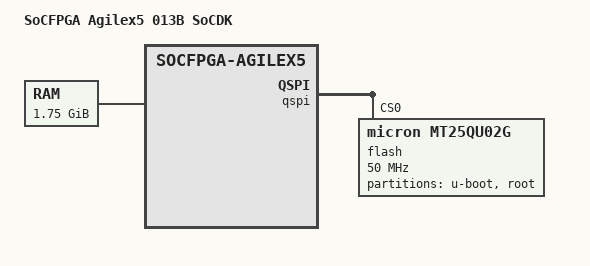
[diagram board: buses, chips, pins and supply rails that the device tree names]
// SPDX-License-Identifier: GPL-2.0-only
/*
 * Copyright (C) 2025, Altera Corporation
 */
#include "socfpga_agilex5_socdk_013b.dts"

/ {
	model = "SoCFPGA Agilex5 013B SoCDK";
	compatible = "intel,socfpga-agilex5-socdk-013b", "intel,socfpga-agilex5";

	chosen {
		stdout-path = "serial0:115200n8";
		bootargs = "console=ttys0,115200 earlycon panic=-1 root=/dev/mtdblock1 \
			rw rootfstype=jffs2 rootwait";
	};

	memory@80000000 {
		device_type = "memory";
		reg = <0 0x80000000 0 0x70000000>;
	};
};

&qspi {
	status = "okay";
	/delete-node/ flash@0;

	flash@0 {
		#address-cells = <1>;
		#size-cells = <1>;
		compatible = "micron,mt25qu02g", "jedec,spi-nor";
		reg = <0>;
		spi-max-frequency = <50000000>;
		m25p,fast-read;
		cdns,page-size = <256>;
		cdns,block-size = <16>;
		cdns,read-delay = <2>;
		cdns,tshsl-ns = <50>;
		cdns,tsd2d-ns = <50>;
		cdns,tchsh-ns = <4>;
		cdns,tslch-ns = <4>;

		partitions {
			compatible = "fixed-partitions";
			#address-cells = <1>;
			#size-cells = <1>;
			rsu-handle = <&qspi_boot>;

			qspi_boot: partition@0 {
				label = "u-boot";
				reg = <0x0 0x0340000>;
			};

			root: partition@3400000 {
				label = "root";
				reg = <0x03400000 0x04FFFFFF>;
			};
		};
	};
};
